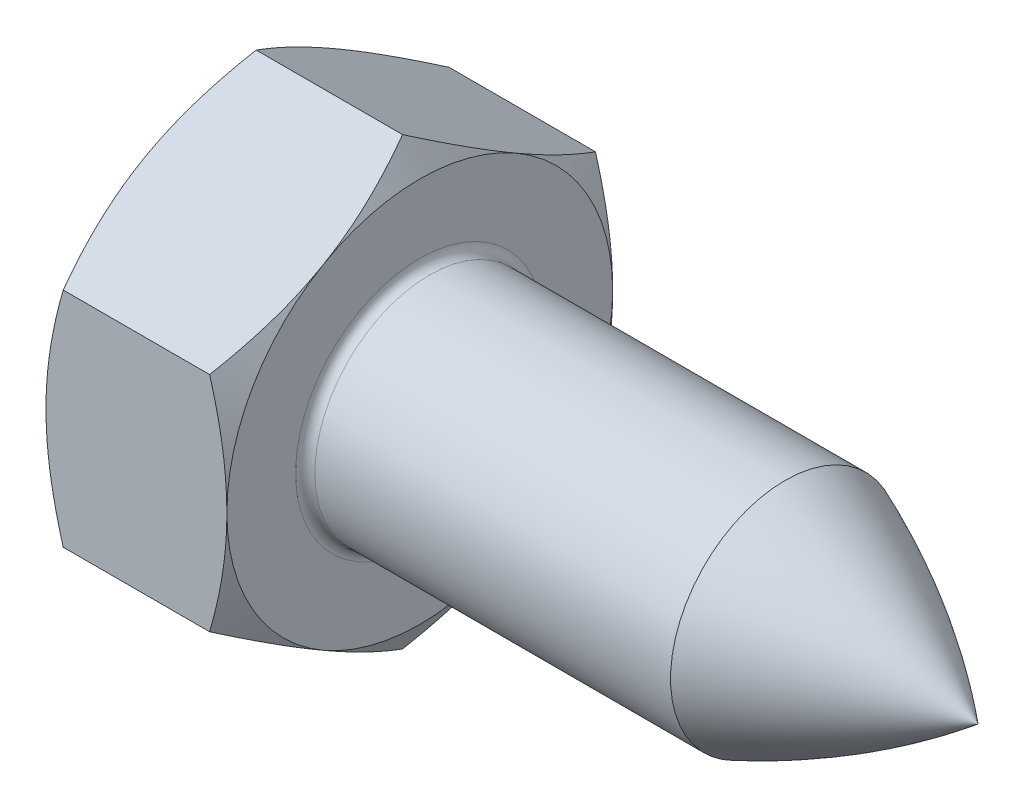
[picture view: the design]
ISO-10303-21;
HEADER;
FILE_DESCRIPTION(('STEP AP214'),'2;1');
FILE_NAME('part.step','',(''),(''),'','','');
FILE_SCHEMA(('AUTOMOTIVE_DESIGN { 1 0 10303 214 1 1 1 1 }'));
ENDSEC;
DATA;
#1=APPLICATION_CONTEXT('core data for automotive mechanical design processes');
#2=APPLICATION_PROTOCOL_DEFINITION('international standard','automotive_design',2000,#1);
#3=PRODUCT_CONTEXT('',#1,'mechanical');
#4=PRODUCT('Part','Part','',(#3));
#5=PRODUCT_RELATED_PRODUCT_CATEGORY('part','',(#4));
#6=PRODUCT_DEFINITION_FORMATION('','',#4);
#7=PRODUCT_DEFINITION_CONTEXT('part definition',#1,'design');
#8=PRODUCT_DEFINITION('design','',#6,#7);
#9=PRODUCT_DEFINITION_SHAPE('','',#8);
#10=(LENGTH_UNIT() NAMED_UNIT(*) SI_UNIT(.MILLI.,.METRE.));
#11=(NAMED_UNIT(*) PLANE_ANGLE_UNIT() SI_UNIT($,.RADIAN.));
#12=(NAMED_UNIT(*) SI_UNIT($,.STERADIAN.) SOLID_ANGLE_UNIT());
#13=UNCERTAINTY_MEASURE_WITH_UNIT(LENGTH_MEASURE(1.E-05),#10,'distance_accuracy_value','');
#14=(GEOMETRIC_REPRESENTATION_CONTEXT(3) GLOBAL_UNCERTAINTY_ASSIGNED_CONTEXT((#13)) GLOBAL_UNIT_ASSIGNED_CONTEXT((#10,
#11,#12)) REPRESENTATION_CONTEXT('',''));
#15=CARTESIAN_POINT('',(0.,0.,0.));
#16=DIRECTION('',(0.,0.,1.));
#17=DIRECTION('',(1.,0.,0.));
#18=AXIS2_PLACEMENT_3D('',#15,#16,#17);
#19=CARTESIAN_POINT('',(-9.54447010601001,0.,0.));
#20=DIRECTION('',(-1.,0.,0.));
#21=DIRECTION('',(0.,0.,1.));
#22=AXIS2_PLACEMENT_3D('',#19,#20,#21);
#23=CYLINDRICAL_SURFACE('',#22,4.75);
#24=CARTESIAN_POINT('',(7.9,0.,0.));
#25=DIRECTION('',(1.,0.,0.));
#26=DIRECTION('',(0.,0.,-1.));
#27=AXIS2_PLACEMENT_3D('',#24,#25,#26);
#28=CIRCLE('',#27,4.75);
#29=CARTESIAN_POINT('',(7.9,0.,-4.75));
#30=VERTEX_POINT('',#29);
#31=EDGE_CURVE('E12',#30,#30,#28,.T.);
#32=ORIENTED_EDGE('',*,*,#31,.T.);
#33=EDGE_LOOP('',(#32));
#34=FACE_BOUND('',#33,.T.);
#35=CARTESIAN_POINT('',(22.65,0.,0.));
#36=DIRECTION('',(1.,0.,0.));
#37=DIRECTION('',(0.,1.,0.));
#38=AXIS2_PLACEMENT_3D('',#35,#36,#37);
#39=CIRCLE('',#38,4.75);
#40=CARTESIAN_POINT('',(22.65,4.75,0.));
#41=VERTEX_POINT('',#40);
#42=EDGE_CURVE('E357',#41,#41,#39,.T.);
#43=ORIENTED_EDGE('',*,*,#42,.F.);
#44=EDGE_LOOP('',(#43));
#45=FACE_BOUND('',#44,.T.);
#46=ADVANCED_FACE('F36',(#34,#45),#23,.T.);
#47=CARTESIAN_POINT('',(7.5,13.856406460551,8.00000000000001));
#48=DIRECTION('',(1.,0.,0.));
#49=DIRECTION('',(0.,0.,-1.));
#50=AXIS2_PLACEMENT_3D('',#47,#48,#49);
#51=PLANE('',#50);
#52=CARTESIAN_POINT('',(7.5,0.,0.));
#53=DIRECTION('',(1.,0.,0.));
#54=DIRECTION('',(0.,0.,-1.));
#55=AXIS2_PLACEMENT_3D('',#52,#53,#54);
#56=CIRCLE('',#55,5.15);
#57=CARTESIAN_POINT('',(7.5,0.,-5.15));
#58=VERTEX_POINT('',#57);
#59=EDGE_CURVE('E45',#58,#58,#56,.F.);
#60=ORIENTED_EDGE('',*,*,#59,.T.);
#61=EDGE_LOOP('',(#60));
#62=FACE_BOUND('',#61,.T.);
#63=CARTESIAN_POINT('',(7.5,0.,0.));
#64=DIRECTION('',(1.,0.,0.));
#65=DIRECTION('',(0.,1.,0.));
#66=AXIS2_PLACEMENT_3D('',#63,#64,#65);
#67=CIRCLE('',#66,8.);
#68=CARTESIAN_POINT('',(7.5,-6.92820323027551,-4.));
#69=VERTEX_POINT('',#68);
#70=CARTESIAN_POINT('',(7.5,0.,-8.));
#71=VERTEX_POINT('',#70);
#72=EDGE_CURVE('E360',#69,#71,#67,.T.);
#73=ORIENTED_EDGE('',*,*,#72,.T.);
#74=CARTESIAN_POINT('',(7.5,6.92820323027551,-4.));
#75=VERTEX_POINT('',#74);
#76=EDGE_CURVE('E356',#71,#75,#67,.T.);
#77=ORIENTED_EDGE('',*,*,#76,.T.);
#78=CARTESIAN_POINT('',(7.5,6.92820323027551,4.));
#79=VERTEX_POINT('',#78);
#80=EDGE_CURVE('E351',#75,#79,#67,.T.);
#81=ORIENTED_EDGE('',*,*,#80,.T.);
#82=CARTESIAN_POINT('',(7.5,0.,8.));
#83=VERTEX_POINT('',#82);
#84=EDGE_CURVE('E52',#79,#83,#67,.T.);
#85=ORIENTED_EDGE('',*,*,#84,.T.);
#86=CARTESIAN_POINT('',(7.5,-6.92820323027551,4.));
#87=VERTEX_POINT('',#86);
#88=EDGE_CURVE('E60',#83,#87,#67,.T.);
#89=ORIENTED_EDGE('',*,*,#88,.T.);
#90=EDGE_CURVE('E354',#87,#69,#67,.T.);
#91=ORIENTED_EDGE('',*,*,#90,.T.);
#92=EDGE_LOOP('',(#73,#77,#81,#85,#89,#91));
#93=FACE_BOUND('',#92,.T.);
#94=ADVANCED_FACE('F146',(#62,#93),#51,.T.);
#95=CARTESIAN_POINT('',(6.78546882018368,0.,0.));
#96=DIRECTION('',(-1.,0.,0.));
#97=DIRECTION('',(0.,-1.,0.));
#98=AXIS2_PLACEMENT_3D('',#95,#96,#97);
#99=CONICAL_SURFACE('',#98,9.23760430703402,1.0471975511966);
#100=CARTESIAN_POINT('',(3.67178635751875,-12.2497439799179,-8.00000000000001));
#101=CARTESIAN_POINT('',(3.84152745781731,-11.8984987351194,-8.00000000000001));
#102=CARTESIAN_POINT('',(4.00958119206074,-11.5464230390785,-8.00000000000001));
#103=CARTESIAN_POINT('',(4.34134970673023,-10.840161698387,-8.00000000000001));
#104=CARTESIAN_POINT('',(4.50506373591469,-10.4859757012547,-8.00000000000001));
#105=CARTESIAN_POINT('',(4.82805107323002,-9.77313142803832,-8.00000000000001));
#106=CARTESIAN_POINT('',(4.98729360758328,-9.41445915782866,-8.00000000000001));
#107=CARTESIAN_POINT('',(5.2989388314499,-8.69416671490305,-8.00000000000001));
#108=CARTESIAN_POINT('',(5.45134187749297,-8.33254669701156,-8.00000000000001));
#109=CARTESIAN_POINT('',(5.74929869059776,-7.60129405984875,-8.00000000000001));
#110=CARTESIAN_POINT('',(5.89474539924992,-7.23161757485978,-8.));
#111=CARTESIAN_POINT('',(6.17424757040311,-6.48790521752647,-8.));
#112=CARTESIAN_POINT('',(6.30830176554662,-6.11386886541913,-8.));
#113=CARTESIAN_POINT('',(6.56141638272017,-5.36160531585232,-8.));
#114=CARTESIAN_POINT('',(6.68050868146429,-4.9833889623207,-8.));
#115=CARTESIAN_POINT('',(6.89983373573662,-4.22159300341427,-8.));
#116=CARTESIAN_POINT('',(7.0000724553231,-3.83801513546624,-8.));
#117=CARTESIAN_POINT('',(7.17681673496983,-3.06517005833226,-8.));
#118=CARTESIAN_POINT('',(7.25331597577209,-2.67590136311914,-8.));
#119=CARTESIAN_POINT('',(7.34642984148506,-2.0885729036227,-8.));
#120=CARTESIAN_POINT('',(7.37386398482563,-1.89220175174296,-8.));
#121=CARTESIAN_POINT('',(7.4209808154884,-1.49853877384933,-8.));
#122=CARTESIAN_POINT('',(7.44066427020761,-1.30124704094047,-8.));
#123=CARTESIAN_POINT('',(7.47175001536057,-0.907261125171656,-8.));
#124=CARTESIAN_POINT('',(7.48320372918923,-0.710571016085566,-8.));
#125=CARTESIAN_POINT('',(7.49776943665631,-0.316882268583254,-8.));
#126=CARTESIAN_POINT('',(7.50088153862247,-0.119883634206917,-8.));
#127=CARTESIAN_POINT('',(7.49868986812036,0.274012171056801,-8.));
#128=CARTESIAN_POINT('',(7.49338845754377,0.470909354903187,-8.));
#129=CARTESIAN_POINT('',(7.47450159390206,0.864308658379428,-8.));
#130=CARTESIAN_POINT('',(7.4609157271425,1.06081075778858,-8.));
#131=CARTESIAN_POINT('',(7.41823147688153,1.53707134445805,-8.));
#132=CARTESIAN_POINT('',(7.38498228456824,1.81646391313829,-8.));
#133=CARTESIAN_POINT('',(7.30358169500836,2.37310809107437,-8.));
#134=CARTESIAN_POINT('',(7.25542623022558,2.65035909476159,-8.));
#135=CARTESIAN_POINT('',(7.14592101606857,3.20249141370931,-8.));
#136=CARTESIAN_POINT('',(7.08455879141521,3.47737023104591,-8.));
#137=CARTESIAN_POINT('',(6.95051229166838,4.02429975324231,-8.));
#138=CARTESIAN_POINT('',(6.87782908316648,4.29635072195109,-8.));
#139=CARTESIAN_POINT('',(6.7209795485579,4.84432510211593,-8.));
#140=CARTESIAN_POINT('',(6.63657541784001,5.12017997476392,-8.));
#141=CARTESIAN_POINT('',(6.4594275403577,5.66897392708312,-8.));
#142=CARTESIAN_POINT('',(6.36668954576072,5.94191487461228,-8.));
#143=CARTESIAN_POINT('',(6.17478953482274,6.48378576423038,-8.));
#144=CARTESIAN_POINT('',(6.07566661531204,6.75272963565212,-8.));
#145=CARTESIAN_POINT('',(5.87160282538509,7.28853074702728,-8.));
#146=CARTESIAN_POINT('',(5.76665960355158,7.55538709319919,-8.));
#147=CARTESIAN_POINT('',(5.65938198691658,7.82127397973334,-8.));
#148=B_SPLINE_CURVE_WITH_KNOTS('',3,(#100,#101,#102,#103,#104,#105,#106,#107,#108,#109,#110,
#111,#112,#113,#114,#115,#116,#117,#118,#119,#120,#121,#122,#123,#124,#125,#126,#127,#128,#129,
#130,#131,#132,#133,#134,#135,#136,#137,#138,#139,#140,#141,#142,#143,#144,#145,#146,#147),
.UNSPECIFIED.,.F.,.F.,(4,2,2,2,2,2,2,2,2,2,2,2,2,2,2,2,2,2,2,2,2,2,2,4),(0.,1.17034358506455,
2.34088846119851,3.51813189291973,4.69531388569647,5.88694801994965,7.07871454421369,
8.26789729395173,9.45670322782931,10.6458253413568,11.2405311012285,11.8351779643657,
12.4260760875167,13.0169665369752,13.6076911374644,14.1984452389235,15.0420672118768,
15.8859195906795,16.7305726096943,17.5751460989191,18.4404219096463,19.3051050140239,
20.1649211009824,21.0250871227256),.UNSPECIFIED.);
#149=CARTESIAN_POINT('',(6.78546882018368,-4.61880215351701,-8.));
#150=VERTEX_POINT('',#149);
#151=EDGE_CURVE('E184',#71,#150,#148,.F.);
#152=ORIENTED_EDGE('',*,*,#151,.F.);
#153=ORIENTED_EDGE('',*,*,#72,.F.);
#154=CARTESIAN_POINT('',(6.78540215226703,-4.61868668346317,-8.0002));
#155=CARTESIAN_POINT('',(6.84400928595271,-4.72021302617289,-7.82435121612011));
#156=CARTESIAN_POINT('',(6.89995659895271,-4.82211789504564,-7.64784680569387));
#157=CARTESIAN_POINT('',(7.00579899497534,-5.02675523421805,-7.29340453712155));
#158=CARTESIAN_POINT('',(7.05569146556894,-5.12948804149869,-7.11546609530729));
#159=CARTESIAN_POINT('',(7.19530720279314,-5.43933133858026,-6.57880176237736));
#160=CARTESIAN_POINT('',(7.27471882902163,-5.64766491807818,-6.21795741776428));
#161=CARTESIAN_POINT('',(7.36783835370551,-5.95943209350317,-5.67796082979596));
#162=CARTESIAN_POINT('',(7.39436541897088,-6.06193429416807,-5.50042181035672));
#163=CARTESIAN_POINT('',(7.43884682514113,-6.26740224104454,-5.14454088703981));
#164=CARTESIAN_POINT('',(7.45680192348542,-6.37036794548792,-4.96619905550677));
#165=CARTESIAN_POINT('',(7.48368435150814,-6.57647664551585,-4.60920831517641));
#166=CARTESIAN_POINT('',(7.49262192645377,-6.67961930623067,-4.4305599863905));
#167=CARTESIAN_POINT('',(7.50127769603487,-6.88599991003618,-4.07309829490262));
#168=CARTESIAN_POINT('',(7.50099617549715,-6.98923785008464,-3.89428493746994));
#169=CARTESIAN_POINT('',(7.49185497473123,-7.18224506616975,-3.5599866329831));
#170=CARTESIAN_POINT('',(7.48411039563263,-7.27202796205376,-3.40447809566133));
#171=CARTESIAN_POINT('',(7.46179886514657,-7.45138347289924,-3.0938252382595));
#172=CARTESIAN_POINT('',(7.44723145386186,-7.5409560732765,-2.93868094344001));
#173=CARTESIAN_POINT('',(7.39363930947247,-7.80932710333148,-2.47384868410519));
#174=CARTESIAN_POINT('',(7.34473135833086,-7.98765049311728,-2.16498351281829));
#175=CARTESIAN_POINT('',(7.22246059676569,-8.34618890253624,-1.54397677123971));
#176=CARTESIAN_POINT('',(7.14857947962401,-8.52635816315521,-1.23191445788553));
#177=CARTESIAN_POINT('',(6.98089985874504,-8.88400987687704,-0.612443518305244));
#178=CARTESIAN_POINT('',(6.88714073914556,-9.06149691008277,-0.305026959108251));
#179=CARTESIAN_POINT('',(6.78540215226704,-9.23771977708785,0.000199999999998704));
#180=B_SPLINE_CURVE_WITH_KNOTS('',3,(#154,#155,#156,#157,#158,#159,#160,#161,#162,#163,#164,
#165,#166,#167,#168,#169,#170,#171,#172,#173,#174,#175,#176,#177,#178,#179),.UNSPECIFIED.,.F.,
.F.,(4,2,2,2,2,2,2,2,2,2,2,2,4),(0.,0.633973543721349,1.26821965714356,2.53934712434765,
3.15934343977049,3.77928496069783,4.39852133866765,5.01773858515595,5.55680239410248,
6.09590254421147,7.17487077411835,8.27776850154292,9.37850115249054),.UNSPECIFIED.);
#181=EDGE_CURVE('E206',#150,#69,#180,.T.);
#182=ORIENTED_EDGE('',*,*,#181,.F.);
#183=EDGE_LOOP('',(#152,#153,#182));
#184=FACE_BOUND('',#183,.T.);
#185=ADVANCED_FACE('F152',(#184),#99,.T.);
#186=ORIENTED_EDGE('',*,*,#76,.F.);
#187=CARTESIAN_POINT('',(6.78546882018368,4.61880215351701,-8.));
#188=VERTEX_POINT('',#187);
#189=EDGE_CURVE('E191',#188,#71,#148,.F.);
#190=ORIENTED_EDGE('',*,*,#189,.F.);
#191=CARTESIAN_POINT('',(6.78540215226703,9.23771977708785,0.000200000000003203));
#192=CARTESIAN_POINT('',(6.8440092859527,9.13619343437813,-0.175648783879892));
#193=CARTESIAN_POINT('',(6.89995659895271,9.03428856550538,-0.35215319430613));
#194=CARTESIAN_POINT('',(7.00579899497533,8.82965122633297,-0.706595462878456));
#195=CARTESIAN_POINT('',(7.05569146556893,8.72691841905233,-0.884533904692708));
#196=CARTESIAN_POINT('',(7.19530720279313,8.41707512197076,-1.42119823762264));
#197=CARTESIAN_POINT('',(7.27471882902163,8.20874154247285,-1.78204258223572));
#198=CARTESIAN_POINT('',(7.36783835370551,7.89697436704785,-2.32203917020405));
#199=CARTESIAN_POINT('',(7.39436541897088,7.79447216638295,-2.49957818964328));
#200=CARTESIAN_POINT('',(7.43884682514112,7.58900421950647,-2.8554591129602));
#201=CARTESIAN_POINT('',(7.45680192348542,7.4860385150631,-3.03380094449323));
#202=CARTESIAN_POINT('',(7.48368435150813,7.27992981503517,-3.39079168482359));
#203=CARTESIAN_POINT('',(7.49262192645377,7.17678715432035,-3.5694400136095));
#204=CARTESIAN_POINT('',(7.50127769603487,6.97040655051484,-3.92690170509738));
#205=CARTESIAN_POINT('',(7.50099617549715,6.86716861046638,-4.10571506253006));
#206=CARTESIAN_POINT('',(7.49185497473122,6.67416139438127,-4.4400133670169));
#207=CARTESIAN_POINT('',(7.48411039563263,6.58437849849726,-4.59552190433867));
#208=CARTESIAN_POINT('',(7.46179886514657,6.40502298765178,-4.90617476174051));
#209=CARTESIAN_POINT('',(7.44723145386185,6.31545038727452,-5.06131905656));
#210=CARTESIAN_POINT('',(7.39363930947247,6.04707935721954,-5.52615131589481));
#211=CARTESIAN_POINT('',(7.34473135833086,5.86875596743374,-5.83501648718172));
#212=CARTESIAN_POINT('',(7.22246059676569,5.51021755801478,-6.4560232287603));
#213=CARTESIAN_POINT('',(7.14857947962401,5.33004829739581,-6.76808554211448));
#214=CARTESIAN_POINT('',(6.98089985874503,4.97239658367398,-7.38755648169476));
#215=CARTESIAN_POINT('',(6.88714073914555,4.79490955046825,-7.69497304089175));
#216=CARTESIAN_POINT('',(6.78540215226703,4.61868668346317,-8.0002));
#217=B_SPLINE_CURVE_WITH_KNOTS('',3,(#191,#192,#193,#194,#195,#196,#197,#198,#199,#200,#201,
#202,#203,#204,#205,#206,#207,#208,#209,#210,#211,#212,#213,#214,#215,#216),.UNSPECIFIED.,.F.,
.F.,(4,2,2,2,2,2,2,2,2,2,2,2,4),(0.,0.633973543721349,1.26821965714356,2.53934712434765,
3.15934343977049,3.77928496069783,4.39852133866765,5.01773858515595,5.55680239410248,
6.09590254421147,7.17487077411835,8.27776850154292,9.37850115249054),.UNSPECIFIED.);
#218=EDGE_CURVE('E213',#75,#188,#217,.T.);
#219=ORIENTED_EDGE('',*,*,#218,.F.);
#220=EDGE_LOOP('',(#186,#190,#219));
#221=FACE_BOUND('',#220,.T.);
#222=ADVANCED_FACE('F519',(#221),#99,.T.);
#223=CARTESIAN_POINT('',(6.78546882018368,-9.23760430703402,0.));
#224=VERTEX_POINT('',#223);
#225=EDGE_CURVE('E336',#69,#224,#180,.T.);
#226=ORIENTED_EDGE('',*,*,#225,.F.);
#227=ORIENTED_EDGE('',*,*,#90,.F.);
#228=CARTESIAN_POINT('',(6.78540215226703,-9.23771977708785,-0.000200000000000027));
#229=CARTESIAN_POINT('',(6.84400928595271,-9.13619343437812,0.175648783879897));
#230=CARTESIAN_POINT('',(6.89995659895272,-9.03428856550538,0.352153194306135));
#231=CARTESIAN_POINT('',(7.00579899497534,-8.82965122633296,0.706595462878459));
#232=CARTESIAN_POINT('',(7.05569146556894,-8.72691841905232,0.884533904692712));
#233=CARTESIAN_POINT('',(7.19530720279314,-8.41707512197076,1.42119823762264));
#234=CARTESIAN_POINT('',(7.27471882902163,-8.20874154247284,1.78204258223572));
#235=CARTESIAN_POINT('',(7.36783835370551,-7.89697436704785,2.32203917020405));
#236=CARTESIAN_POINT('',(7.39436541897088,-7.79447216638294,2.49957818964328));
#237=CARTESIAN_POINT('',(7.43884682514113,-7.58900421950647,2.8554591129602));
#238=CARTESIAN_POINT('',(7.45680192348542,-7.4860385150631,3.03380094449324));
#239=CARTESIAN_POINT('',(7.48368435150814,-7.27992981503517,3.39079168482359));
#240=CARTESIAN_POINT('',(7.49262192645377,-7.17678715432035,3.5694400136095));
#241=CARTESIAN_POINT('',(7.50127769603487,-6.97040655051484,3.92690170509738));
#242=CARTESIAN_POINT('',(7.50099617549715,-6.86716861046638,4.10571506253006));
#243=CARTESIAN_POINT('',(7.49185497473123,-6.67416139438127,4.4400133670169));
#244=CARTESIAN_POINT('',(7.48411039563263,-6.58437849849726,4.59552190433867));
#245=CARTESIAN_POINT('',(7.46179886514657,-6.40502298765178,4.90617476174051));
#246=CARTESIAN_POINT('',(7.44723145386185,-6.31545038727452,5.06131905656));
#247=CARTESIAN_POINT('',(7.39363930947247,-6.04707935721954,5.52615131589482));
#248=CARTESIAN_POINT('',(7.34473135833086,-5.86875596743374,5.83501648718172));
#249=CARTESIAN_POINT('',(7.22246059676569,-5.51021755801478,6.4560232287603));
#250=CARTESIAN_POINT('',(7.14857947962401,-5.33004829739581,6.76808554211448));
#251=CARTESIAN_POINT('',(6.98089985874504,-4.97239658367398,7.38755648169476));
#252=CARTESIAN_POINT('',(6.88714073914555,-4.79490955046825,7.69497304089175));
#253=CARTESIAN_POINT('',(6.78540215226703,-4.61868668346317,8.0002));
#254=B_SPLINE_CURVE_WITH_KNOTS('',3,(#228,#229,#230,#231,#232,#233,#234,#235,#236,#237,#238,
#239,#240,#241,#242,#243,#244,#245,#246,#247,#248,#249,#250,#251,#252,#253),.UNSPECIFIED.,.F.,
.F.,(4,2,2,2,2,2,2,2,2,2,2,2,4),(0.,0.63397354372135,1.26821965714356,2.53934712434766,
3.15934343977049,3.77928496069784,4.39852133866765,5.01773858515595,5.55680239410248,
6.09590254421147,7.17487077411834,8.27776850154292,9.37850115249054),.UNSPECIFIED.);
#255=EDGE_CURVE('E218',#224,#87,#254,.T.);
#256=ORIENTED_EDGE('',*,*,#255,.F.);
#257=EDGE_LOOP('',(#226,#227,#256));
#258=FACE_BOUND('',#257,.T.);
#259=ADVANCED_FACE('F199',(#258),#99,.T.);
#260=CARTESIAN_POINT('',(6.78546882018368,-4.61880215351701,8.));
#261=VERTEX_POINT('',#260);
#262=EDGE_CURVE('E346',#87,#261,#254,.T.);
#263=ORIENTED_EDGE('',*,*,#262,.F.);
#264=ORIENTED_EDGE('',*,*,#88,.F.);
#265=CARTESIAN_POINT('',(3.67178635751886,-12.2497439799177,7.99999999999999));
#266=CARTESIAN_POINT('',(3.84152745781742,-11.8984987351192,8.));
#267=CARTESIAN_POINT('',(4.00958119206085,-11.5464230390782,8.));
#268=CARTESIAN_POINT('',(4.34134970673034,-10.8401616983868,8.));
#269=CARTESIAN_POINT('',(4.50506373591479,-10.4859757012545,8.));
#270=CARTESIAN_POINT('',(4.82805107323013,-9.7731314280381,8.));
#271=CARTESIAN_POINT('',(4.98729360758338,-9.41445915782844,8.));
#272=CARTESIAN_POINT('',(5.29893883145,-8.69416671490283,8.));
#273=CARTESIAN_POINT('',(5.45134187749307,-8.33254669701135,8.));
#274=CARTESIAN_POINT('',(5.74929869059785,-7.60129405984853,8.));
#275=CARTESIAN_POINT('',(5.89474539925,-7.23161757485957,8.));
#276=CARTESIAN_POINT('',(6.17424757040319,-6.48790521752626,8.));
#277=CARTESIAN_POINT('',(6.3083017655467,-6.11386886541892,8.));
#278=CARTESIAN_POINT('',(6.56141638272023,-5.36160531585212,8.));
#279=CARTESIAN_POINT('',(6.68050868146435,-4.9833889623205,8.));
#280=CARTESIAN_POINT('',(6.89983373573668,-4.22159300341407,8.));
#281=CARTESIAN_POINT('',(7.00007245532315,-3.83801513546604,8.));
#282=CARTESIAN_POINT('',(7.17681673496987,-3.06517005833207,8.));
#283=CARTESIAN_POINT('',(7.25331597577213,-2.67590136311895,8.));
#284=CARTESIAN_POINT('',(7.34642984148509,-2.0885729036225,8.));
#285=CARTESIAN_POINT('',(7.37386398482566,-1.89220175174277,8.));
#286=CARTESIAN_POINT('',(7.42098081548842,-1.49853877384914,8.));
#287=CARTESIAN_POINT('',(7.44066427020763,-1.30124704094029,8.));
#288=CARTESIAN_POINT('',(7.47175001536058,-0.907261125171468,8.));
#289=CARTESIAN_POINT('',(7.48320372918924,-0.710571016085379,8.));
#290=CARTESIAN_POINT('',(7.49776943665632,-0.31688226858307,8.));
#291=CARTESIAN_POINT('',(7.50088153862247,-0.119883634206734,8.));
#292=CARTESIAN_POINT('',(7.49868986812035,0.274012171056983,8.));
#293=CARTESIAN_POINT('',(7.49338845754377,0.470909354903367,8.));
#294=CARTESIAN_POINT('',(7.47450159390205,0.864308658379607,8.));
#295=CARTESIAN_POINT('',(7.46091572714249,1.06081075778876,8.));
#296=CARTESIAN_POINT('',(7.41823147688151,1.53707134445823,8.));
#297=CARTESIAN_POINT('',(7.38498228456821,1.81646391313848,8.));
#298=CARTESIAN_POINT('',(7.30358169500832,2.37310809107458,8.));
#299=CARTESIAN_POINT('',(7.25542623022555,2.6503590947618,8.));
#300=CARTESIAN_POINT('',(7.14592101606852,3.20249141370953,8.));
#301=CARTESIAN_POINT('',(7.08455879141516,3.47737023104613,8.));
#302=CARTESIAN_POINT('',(6.95051229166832,4.02429975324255,8.));
#303=CARTESIAN_POINT('',(6.87782908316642,4.29635072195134,8.));
#304=CARTESIAN_POINT('',(6.72097954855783,4.84432510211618,8.));
#305=CARTESIAN_POINT('',(6.63657541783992,5.12017997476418,8.));
#306=CARTESIAN_POINT('',(6.4594275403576,5.66897392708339,8.));
#307=CARTESIAN_POINT('',(6.36668954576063,5.94191487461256,8.));
#308=CARTESIAN_POINT('',(6.17478953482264,6.48378576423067,8.));
#309=CARTESIAN_POINT('',(6.07566661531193,6.75272963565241,8.));
#310=CARTESIAN_POINT('',(5.87160282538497,7.28853074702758,8.));
#311=CARTESIAN_POINT('',(5.76665960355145,7.5553870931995,8.));
#312=CARTESIAN_POINT('',(5.65938198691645,7.82127397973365,8.));
#313=B_SPLINE_CURVE_WITH_KNOTS('',3,(#265,#266,#267,#268,#269,#270,#271,#272,#273,#274,#275,
#276,#277,#278,#279,#280,#281,#282,#283,#284,#285,#286,#287,#288,#289,#290,#291,#292,#293,#294,
#295,#296,#297,#298,#299,#300,#301,#302,#303,#304,#305,#306,#307,#308,#309,#310,#311,#312),
.UNSPECIFIED.,.F.,.F.,(4,2,2,2,2,2,2,2,2,2,2,2,2,2,2,2,2,2,2,2,2,2,2,4),(0.,1.17034358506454,
2.3408884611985,3.51813189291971,4.69531388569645,5.88694801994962,7.07871454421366,
8.26789729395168,9.45670322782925,10.6458253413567,11.2405311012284,11.8351779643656,
12.4260760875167,13.0169665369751,13.6076911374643,14.1984452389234,15.0420672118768,
15.8859195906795,16.7305726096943,17.5751460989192,18.4404219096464,19.305105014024,
20.1649211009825,21.0250871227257),.UNSPECIFIED.);
#314=EDGE_CURVE('E344',#261,#83,#313,.T.);
#315=ORIENTED_EDGE('',*,*,#314,.F.);
#316=EDGE_LOOP('',(#263,#264,#315));
#317=FACE_BOUND('',#316,.T.);
#318=ADVANCED_FACE('F195',(#317),#99,.T.);
#319=ORIENTED_EDGE('',*,*,#84,.F.);
#320=CARTESIAN_POINT('',(6.78540215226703,4.61868668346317,8.0002));
#321=CARTESIAN_POINT('',(6.84400928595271,4.72021302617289,7.82435121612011));
#322=CARTESIAN_POINT('',(6.89995659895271,4.82211789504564,7.64784680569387));
#323=CARTESIAN_POINT('',(7.00579899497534,5.02675523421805,7.29340453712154));
#324=CARTESIAN_POINT('',(7.05569146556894,5.12948804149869,7.11546609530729));
#325=CARTESIAN_POINT('',(7.19530720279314,5.43933133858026,6.57880176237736));
#326=CARTESIAN_POINT('',(7.27471882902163,5.64766491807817,6.21795741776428));
#327=CARTESIAN_POINT('',(7.36783835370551,5.95943209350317,5.67796082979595));
#328=CARTESIAN_POINT('',(7.39436541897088,6.06193429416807,5.50042181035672));
#329=CARTESIAN_POINT('',(7.43884682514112,6.26740224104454,5.14454088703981));
#330=CARTESIAN_POINT('',(7.45680192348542,6.37036794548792,4.96619905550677));
#331=CARTESIAN_POINT('',(7.48368435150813,6.57647664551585,4.60920831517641));
#332=CARTESIAN_POINT('',(7.49262192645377,6.67961930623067,4.4305599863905));
#333=CARTESIAN_POINT('',(7.50127769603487,6.88599991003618,4.07309829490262));
#334=CARTESIAN_POINT('',(7.50099617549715,6.98923785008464,3.89428493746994));
#335=CARTESIAN_POINT('',(7.49185497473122,7.18224506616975,3.5599866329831));
#336=CARTESIAN_POINT('',(7.48411039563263,7.27202796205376,3.40447809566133));
#337=CARTESIAN_POINT('',(7.46179886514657,7.45138347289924,3.09382523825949));
#338=CARTESIAN_POINT('',(7.44723145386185,7.5409560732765,2.93868094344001));
#339=CARTESIAN_POINT('',(7.39363930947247,7.80932710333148,2.47384868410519));
#340=CARTESIAN_POINT('',(7.34473135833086,7.98765049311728,2.16498351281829));
#341=CARTESIAN_POINT('',(7.22246059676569,8.34618890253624,1.54397677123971));
#342=CARTESIAN_POINT('',(7.14857947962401,8.52635816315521,1.23191445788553));
#343=CARTESIAN_POINT('',(6.98089985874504,8.88400987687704,0.612443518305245));
#344=CARTESIAN_POINT('',(6.88714073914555,9.06149691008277,0.305026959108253));
#345=CARTESIAN_POINT('',(6.78540215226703,9.23771977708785,-0.000199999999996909));
#346=B_SPLINE_CURVE_WITH_KNOTS('',3,(#320,#321,#322,#323,#324,#325,#326,#327,#328,#329,#330,
#331,#332,#333,#334,#335,#336,#337,#338,#339,#340,#341,#342,#343,#344,#345),.UNSPECIFIED.,.F.,
.F.,(4,2,2,2,2,2,2,2,2,2,2,2,4),(0.,0.633973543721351,1.26821965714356,2.53934712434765,
3.15934343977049,3.77928496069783,4.39852133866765,5.01773858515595,5.55680239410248,
6.09590254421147,7.17487077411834,8.27776850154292,9.37850115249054),.UNSPECIFIED.);
#347=CARTESIAN_POINT('',(6.78546882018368,4.618802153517,8.));
#348=VERTEX_POINT('',#347);
#349=EDGE_CURVE('E229',#348,#79,#346,.T.);
#350=ORIENTED_EDGE('',*,*,#349,.F.);
#351=EDGE_CURVE('E230',#83,#348,#313,.T.);
#352=ORIENTED_EDGE('',*,*,#351,.F.);
#353=EDGE_LOOP('',(#319,#350,#352));
#354=FACE_BOUND('',#353,.T.);
#355=ADVANCED_FACE('F198',(#354),#99,.T.);
#356=ORIENTED_EDGE('',*,*,#80,.F.);
#357=CARTESIAN_POINT('',(6.78546882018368,9.23760430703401,0.));
#358=VERTEX_POINT('',#357);
#359=EDGE_CURVE('E348',#358,#75,#217,.T.);
#360=ORIENTED_EDGE('',*,*,#359,.F.);
#361=EDGE_CURVE('E223',#79,#358,#346,.T.);
#362=ORIENTED_EDGE('',*,*,#361,.F.);
#363=EDGE_LOOP('',(#356,#360,#362));
#364=FACE_BOUND('',#363,.T.);
#365=ADVANCED_FACE('F164',(#364),#99,.T.);
#366=CARTESIAN_POINT('',(0.,13.856406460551,8.00000000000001));
#367=DIRECTION('',(1.,0.,0.));
#368=DIRECTION('',(0.,0.,-1.));
#369=AXIS2_PLACEMENT_3D('',#366,#367,#368);
#370=PLANE('',#369);
#371=CARTESIAN_POINT('',(0.,0.,0.));
#372=DIRECTION('',(1.,0.,0.));
#373=DIRECTION('',(0.,0.,-1.));
#374=AXIS2_PLACEMENT_3D('',#371,#372,#373);
#375=CIRCLE('',#374,6.66666666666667);
#376=CARTESIAN_POINT('',(0.,0.,-6.66666666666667));
#377=VERTEX_POINT('',#376);
#378=EDGE_CURVE('E40',#377,#377,#375,.T.);
#379=ORIENTED_EDGE('',*,*,#378,.T.);
#380=EDGE_LOOP('',(#379));
#381=FACE_BOUND('',#380,.T.);
#382=CARTESIAN_POINT('',(0.,0.,0.));
#383=DIRECTION('',(1.,0.,0.));
#384=DIRECTION('',(0.,0.,-1.));
#385=AXIS2_PLACEMENT_3D('',#382,#383,#384);
#386=CIRCLE('',#385,8.);
#387=CARTESIAN_POINT('',(0.,6.92820323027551,-4.));
#388=VERTEX_POINT('',#387);
#389=CARTESIAN_POINT('',(0.,0.,-8.));
#390=VERTEX_POINT('',#389);
#391=EDGE_CURVE('E193',#388,#390,#386,.F.);
#392=ORIENTED_EDGE('',*,*,#391,.T.);
#393=CARTESIAN_POINT('',(0.,-6.92820323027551,-4.));
#394=VERTEX_POINT('',#393);
#395=EDGE_CURVE('E192',#390,#394,#386,.F.);
#396=ORIENTED_EDGE('',*,*,#395,.T.);
#397=CARTESIAN_POINT('',(0.,-6.92820323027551,4.));
#398=VERTEX_POINT('',#397);
#399=EDGE_CURVE('E286',#394,#398,#386,.F.);
#400=ORIENTED_EDGE('',*,*,#399,.T.);
#401=CARTESIAN_POINT('',(0.,0.,8.));
#402=VERTEX_POINT('',#401);
#403=EDGE_CURVE('E285',#398,#402,#386,.F.);
#404=ORIENTED_EDGE('',*,*,#403,.T.);
#405=CARTESIAN_POINT('',(0.,0.,0.));
#406=DIRECTION('',(1.,0.,0.));
#407=DIRECTION('',(0.,1.,0.));
#408=AXIS2_PLACEMENT_3D('',#405,#406,#407);
#409=CIRCLE('',#408,8.);
#410=CARTESIAN_POINT('',(0.,6.92820323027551,4.));
#411=VERTEX_POINT('',#410);
#412=EDGE_CURVE('E296',#411,#402,#409,.T.);
#413=ORIENTED_EDGE('',*,*,#412,.F.);
#414=EDGE_CURVE('E279',#411,#388,#386,.F.);
#415=ORIENTED_EDGE('',*,*,#414,.T.);
#416=EDGE_LOOP('',(#392,#396,#400,#404,#413,#415));
#417=FACE_BOUND('',#416,.T.);
#418=ADVANCED_FACE('F160',(#381,#417),#370,.F.);
#419=CARTESIAN_POINT('',(0.,0.,0.));
#420=DIRECTION('',(1.,0.,0.));
#421=DIRECTION('',(0.,1.,0.));
#422=AXIS2_PLACEMENT_3D('',#419,#420,#421);
#423=CONICAL_SURFACE('',#422,8.,1.0471975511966);
#424=ORIENTED_EDGE('',*,*,#414,.F.);
#425=CARTESIAN_POINT('',(0.714597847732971,9.23771977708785,-0.000199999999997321));
#426=CARTESIAN_POINT('',(0.655990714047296,9.13619343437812,0.175648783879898));
#427=CARTESIAN_POINT('',(0.600043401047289,9.03428856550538,0.352153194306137));
#428=CARTESIAN_POINT('',(0.494201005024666,8.82965122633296,0.706595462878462));
#429=CARTESIAN_POINT('',(0.444308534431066,8.72691841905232,0.884533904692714));
#430=CARTESIAN_POINT('',(0.304692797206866,8.41707512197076,1.42119823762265));
#431=CARTESIAN_POINT('',(0.225281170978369,8.20874154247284,1.78204258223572));
#432=CARTESIAN_POINT('',(0.132161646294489,7.89697436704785,2.32203917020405));
#433=CARTESIAN_POINT('',(0.105634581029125,7.79447216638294,2.49957818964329));
#434=CARTESIAN_POINT('',(0.061153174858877,7.58900421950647,2.8554591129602));
#435=CARTESIAN_POINT('',(0.0431980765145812,7.4860385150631,3.03380094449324));
#436=CARTESIAN_POINT('',(0.0163156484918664,7.27992981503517,3.39079168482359));
#437=CARTESIAN_POINT('',(0.00737807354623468,7.17678715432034,3.5694400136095));
#438=CARTESIAN_POINT('',(-0.00127769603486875,6.97040655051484,3.92690170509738));
#439=CARTESIAN_POINT('',(-0.000996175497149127,6.86716861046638,4.10571506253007));
#440=CARTESIAN_POINT('',(0.00814502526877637,6.67416139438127,4.44001336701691));
#441=CARTESIAN_POINT('',(0.0158896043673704,6.58437849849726,4.59552190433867));
#442=CARTESIAN_POINT('',(0.0382011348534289,6.40502298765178,4.90617476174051));
#443=CARTESIAN_POINT('',(0.0527685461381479,6.31545038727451,5.06131905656));
#444=CARTESIAN_POINT('',(0.106360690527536,6.04707935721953,5.52615131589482));
#445=CARTESIAN_POINT('',(0.155268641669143,5.86875596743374,5.83501648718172));
#446=CARTESIAN_POINT('',(0.277539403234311,5.51021755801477,6.4560232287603));
#447=CARTESIAN_POINT('',(0.351420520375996,5.3300482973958,6.76808554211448));
#448=CARTESIAN_POINT('',(0.519100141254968,4.97239658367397,7.38755648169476));
#449=CARTESIAN_POINT('',(0.612859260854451,4.79490955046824,7.69497304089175));
#450=CARTESIAN_POINT('',(0.714597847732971,4.61868668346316,8.0002));
#451=B_SPLINE_CURVE_WITH_KNOTS('',3,(#425,#426,#427,#428,#429,#430,#431,#432,#433,#434,#435,
#436,#437,#438,#439,#440,#441,#442,#443,#444,#445,#446,#447,#448,#449,#450),.UNSPECIFIED.,.F.,
.F.,(4,2,2,2,2,2,2,2,2,2,2,2,4),(0.,0.63397354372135,1.26821965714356,2.53934712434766,
3.15934343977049,3.77928496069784,4.39852133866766,5.01773858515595,5.55680239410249,
6.09590254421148,7.17487077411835,8.27776850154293,9.37850115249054),.UNSPECIFIED.);
#452=CARTESIAN_POINT('',(0.71453117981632,9.23760430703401,0.));
#453=VERTEX_POINT('',#452);
#454=EDGE_CURVE('E251',#453,#411,#451,.T.);
#455=ORIENTED_EDGE('',*,*,#454,.F.);
#456=CARTESIAN_POINT('',(0.714597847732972,4.61868668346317,-8.0002));
#457=CARTESIAN_POINT('',(0.655990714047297,4.7202130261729,-7.8243512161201));
#458=CARTESIAN_POINT('',(0.60004340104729,4.82211789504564,-7.64784680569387));
#459=CARTESIAN_POINT('',(0.494201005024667,5.02675523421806,-7.29340453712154));
#460=CARTESIAN_POINT('',(0.444308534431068,5.1294880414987,-7.11546609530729));
#461=CARTESIAN_POINT('',(0.304692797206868,5.43933133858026,-6.57880176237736));
#462=CARTESIAN_POINT('',(0.22528117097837,5.64766491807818,-6.21795741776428));
#463=CARTESIAN_POINT('',(0.132161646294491,5.95943209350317,-5.67796082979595));
#464=CARTESIAN_POINT('',(0.105634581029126,6.06193429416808,-5.50042181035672));
#465=CARTESIAN_POINT('',(0.0611531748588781,6.26740224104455,-5.1445408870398));
#466=CARTESIAN_POINT('',(0.043198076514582,6.37036794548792,-4.96619905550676));
#467=CARTESIAN_POINT('',(0.0163156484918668,6.57647664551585,-4.60920831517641));
#468=CARTESIAN_POINT('',(0.00737807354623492,6.67961930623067,-4.4305599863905));
#469=CARTESIAN_POINT('',(-0.0012776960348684,6.88599991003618,-4.07309829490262));
#470=CARTESIAN_POINT('',(-0.000996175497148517,6.98923785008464,-3.89428493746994));
#471=CARTESIAN_POINT('',(0.00814502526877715,7.18224506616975,-3.5599866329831));
#472=CARTESIAN_POINT('',(0.0158896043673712,7.27202796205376,-3.40447809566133));
#473=CARTESIAN_POINT('',(0.0382011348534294,7.45138347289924,-3.09382523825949));
#474=CARTESIAN_POINT('',(0.0527685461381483,7.5409560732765,-2.93868094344));
#475=CARTESIAN_POINT('',(0.106360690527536,7.80932710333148,-2.47384868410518));
#476=CARTESIAN_POINT('',(0.155268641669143,7.98765049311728,-2.16498351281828));
#477=CARTESIAN_POINT('',(0.277539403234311,8.34618890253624,-1.5439767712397));
#478=CARTESIAN_POINT('',(0.351420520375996,8.52635816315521,-1.23191445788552));
#479=CARTESIAN_POINT('',(0.519100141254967,8.88400987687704,-0.612443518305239));
#480=CARTESIAN_POINT('',(0.61285926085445,9.06149691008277,-0.305026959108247));
#481=CARTESIAN_POINT('',(0.71459784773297,9.23771977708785,0.000200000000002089));
#482=B_SPLINE_CURVE_WITH_KNOTS('',3,(#456,#457,#458,#459,#460,#461,#462,#463,#464,#465,#466,
#467,#468,#469,#470,#471,#472,#473,#474,#475,#476,#477,#478,#479,#480,#481),.UNSPECIFIED.,.F.,
.F.,(4,2,2,2,2,2,2,2,2,2,2,2,4),(0.,0.633973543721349,1.26821965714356,2.53934712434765,
3.15934343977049,3.77928496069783,4.39852133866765,5.01773858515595,5.55680239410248,
6.09590254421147,7.17487077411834,8.27776850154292,9.37850115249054),.UNSPECIFIED.);
#483=EDGE_CURVE('E258',#388,#453,#482,.T.);
#484=ORIENTED_EDGE('',*,*,#483,.F.);
#485=EDGE_LOOP('',(#424,#455,#484));
#486=FACE_BOUND('',#485,.T.);
#487=ADVANCED_FACE('F163',(#486),#423,.T.);
#488=ORIENTED_EDGE('',*,*,#412,.T.);
#489=CARTESIAN_POINT('',(3.82821364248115,-12.2497439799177,7.99999999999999));
#490=CARTESIAN_POINT('',(3.65847254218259,-11.8984987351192,8.));
#491=CARTESIAN_POINT('',(3.49041880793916,-11.5464230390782,8.));
#492=CARTESIAN_POINT('',(3.15865029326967,-10.8401616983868,8.));
#493=CARTESIAN_POINT('',(2.99493626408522,-10.4859757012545,8.));
#494=CARTESIAN_POINT('',(2.67194892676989,-9.7731314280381,8.));
#495=CARTESIAN_POINT('',(2.51270639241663,-9.41445915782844,8.));
#496=CARTESIAN_POINT('',(2.20106116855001,-8.69416671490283,8.));
#497=CARTESIAN_POINT('',(2.04865812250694,-8.33254669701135,8.));
#498=CARTESIAN_POINT('',(1.75070130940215,-7.60129405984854,8.));
#499=CARTESIAN_POINT('',(1.60525460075,-7.23161757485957,8.));
#500=CARTESIAN_POINT('',(1.32575242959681,-6.48790521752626,8.));
#501=CARTESIAN_POINT('',(1.19169823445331,-6.11386886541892,8.));
#502=CARTESIAN_POINT('',(0.938583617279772,-5.36160531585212,8.));
#503=CARTESIAN_POINT('',(0.819491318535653,-4.9833889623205,8.));
#504=CARTESIAN_POINT('',(0.600166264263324,-4.22159300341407,8.));
#505=CARTESIAN_POINT('',(0.49992754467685,-3.83801513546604,8.));
#506=CARTESIAN_POINT('',(0.323183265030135,-3.06517005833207,8.));
#507=CARTESIAN_POINT('',(0.246684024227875,-2.67590136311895,8.));
#508=CARTESIAN_POINT('',(0.15357015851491,-2.0885729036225,8.));
#509=CARTESIAN_POINT('',(0.126136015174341,-1.89220175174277,8.));
#510=CARTESIAN_POINT('',(0.0790191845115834,-1.49853877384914,8.));
#511=CARTESIAN_POINT('',(0.0593357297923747,-1.30124704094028,8.));
#512=CARTESIAN_POINT('',(0.0282499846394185,-0.907261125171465,8.));
#513=CARTESIAN_POINT('',(0.0167962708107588,-0.710571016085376,8.));
#514=CARTESIAN_POINT('',(0.00223056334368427,-0.316882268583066,8.));
#515=CARTESIAN_POINT('',(-0.00088153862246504,-0.11988363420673,8.));
#516=CARTESIAN_POINT('',(0.00131013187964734,0.274012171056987,8.));
#517=CARTESIAN_POINT('',(0.00661154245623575,0.470909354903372,8.));
#518=CARTESIAN_POINT('',(0.0254984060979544,0.864308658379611,8.));
#519=CARTESIAN_POINT('',(0.0390842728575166,1.06081075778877,8.));
#520=CARTESIAN_POINT('',(0.0817685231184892,1.53707134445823,8.));
#521=CARTESIAN_POINT('',(0.115017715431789,1.81646391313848,8.));
#522=CARTESIAN_POINT('',(0.196418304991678,2.37310809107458,8.));
#523=CARTESIAN_POINT('',(0.244573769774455,2.6503590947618,8.));
#524=CARTESIAN_POINT('',(0.354078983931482,3.20249141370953,8.));
#525=CARTESIAN_POINT('',(0.415441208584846,3.47737023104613,8.));
#526=CARTESIAN_POINT('',(0.549487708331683,4.02429975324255,8.));
#527=CARTESIAN_POINT('',(0.622170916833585,4.29635072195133,8.));
#528=CARTESIAN_POINT('',(0.779020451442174,4.84432510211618,8.));
#529=CARTESIAN_POINT('',(0.863424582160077,5.12017997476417,8.));
#530=CARTESIAN_POINT('',(1.0405724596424,5.66897392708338,8.));
#531=CARTESIAN_POINT('',(1.13331045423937,5.94191487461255,8.));
#532=CARTESIAN_POINT('',(1.32521046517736,6.48378576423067,8.));
#533=CARTESIAN_POINT('',(1.42433338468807,6.75272963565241,8.));
#534=CARTESIAN_POINT('',(1.62839717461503,7.28853074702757,8.));
#535=CARTESIAN_POINT('',(1.73334039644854,7.55538709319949,8.));
#536=CARTESIAN_POINT('',(1.84061801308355,7.82127397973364,8.));
#537=B_SPLINE_CURVE_WITH_KNOTS('',3,(#489,#490,#491,#492,#493,#494,#495,#496,#497,#498,#499,
#500,#501,#502,#503,#504,#505,#506,#507,#508,#509,#510,#511,#512,#513,#514,#515,#516,#517,#518,
#519,#520,#521,#522,#523,#524,#525,#526,#527,#528,#529,#530,#531,#532,#533,#534,#535,#536),
.UNSPECIFIED.,.F.,.F.,(4,2,2,2,2,2,2,2,2,2,2,2,2,2,2,2,2,2,2,2,2,2,2,4),(0.,1.17034358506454,
2.34088846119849,3.51813189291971,4.69531388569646,5.88694801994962,7.07871454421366,
8.26789729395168,9.45670322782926,10.6458253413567,11.2405311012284,11.8351779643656,
12.4260760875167,13.0169665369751,13.6076911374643,14.1984452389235,15.0420672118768,
15.8859195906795,16.7305726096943,17.5751460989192,18.4404219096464,19.305105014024,
20.1649211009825,21.0250871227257),.UNSPECIFIED.);
#538=CARTESIAN_POINT('',(0.71453117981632,4.61880215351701,8.));
#539=VERTEX_POINT('',#538);
#540=EDGE_CURVE('E252',#539,#402,#537,.F.);
#541=ORIENTED_EDGE('',*,*,#540,.F.);
#542=EDGE_CURVE('E244',#411,#539,#451,.T.);
#543=ORIENTED_EDGE('',*,*,#542,.F.);
#544=EDGE_LOOP('',(#488,#541,#543));
#545=FACE_BOUND('',#544,.T.);
#546=ADVANCED_FACE('F477',(#545),#423,.T.);
#547=ORIENTED_EDGE('',*,*,#403,.F.);
#548=CARTESIAN_POINT('',(0.714597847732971,-4.61868668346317,8.0002));
#549=CARTESIAN_POINT('',(0.655990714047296,-4.7202130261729,7.8243512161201));
#550=CARTESIAN_POINT('',(0.600043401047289,-4.82211789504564,7.64784680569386));
#551=CARTESIAN_POINT('',(0.494201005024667,-5.02675523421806,7.29340453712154));
#552=CARTESIAN_POINT('',(0.444308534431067,-5.1294880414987,7.11546609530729));
#553=CARTESIAN_POINT('',(0.304692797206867,-5.43933133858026,6.57880176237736));
#554=CARTESIAN_POINT('',(0.225281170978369,-5.64766491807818,6.21795741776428));
#555=CARTESIAN_POINT('',(0.13216164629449,-5.95943209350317,5.67796082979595));
#556=CARTESIAN_POINT('',(0.105634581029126,-6.06193429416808,5.50042181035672));
#557=CARTESIAN_POINT('',(0.0611531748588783,-6.26740224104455,5.1445408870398));
#558=CARTESIAN_POINT('',(0.0431980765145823,-6.37036794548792,4.96619905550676));
#559=CARTESIAN_POINT('',(0.0163156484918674,-6.57647664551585,4.60920831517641));
#560=CARTESIAN_POINT('',(0.00737807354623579,-6.67961930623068,4.4305599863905));
#561=CARTESIAN_POINT('',(-0.00127769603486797,-6.88599991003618,4.07309829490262));
#562=CARTESIAN_POINT('',(-0.000996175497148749,-6.98923785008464,3.89428493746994));
#563=CARTESIAN_POINT('',(0.00814502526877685,-7.18224506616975,3.5599866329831));
#564=CARTESIAN_POINT('',(0.0158896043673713,-7.27202796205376,3.40447809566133));
#565=CARTESIAN_POINT('',(0.0382011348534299,-7.45138347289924,3.09382523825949));
#566=CARTESIAN_POINT('',(0.0527685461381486,-7.5409560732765,2.93868094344));
#567=CARTESIAN_POINT('',(0.106360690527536,-7.80932710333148,2.47384868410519));
#568=CARTESIAN_POINT('',(0.155268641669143,-7.98765049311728,2.16498351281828));
#569=CARTESIAN_POINT('',(0.277539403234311,-8.34618890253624,1.5439767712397));
#570=CARTESIAN_POINT('',(0.351420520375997,-8.52635816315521,1.23191445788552));
#571=CARTESIAN_POINT('',(0.519100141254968,-8.88400987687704,0.612443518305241));
#572=CARTESIAN_POINT('',(0.612859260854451,-9.06149691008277,0.305026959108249));
#573=CARTESIAN_POINT('',(0.714597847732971,-9.23771977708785,-0.000199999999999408));
#574=B_SPLINE_CURVE_WITH_KNOTS('',3,(#548,#549,#550,#551,#552,#553,#554,#555,#556,#557,#558,
#559,#560,#561,#562,#563,#564,#565,#566,#567,#568,#569,#570,#571,#572,#573),.UNSPECIFIED.,.F.,
.F.,(4,2,2,2,2,2,2,2,2,2,2,2,4),(0.,0.633973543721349,1.26821965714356,2.53934712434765,
3.15934343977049,3.77928496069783,4.39852133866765,5.01773858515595,5.55680239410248,
6.09590254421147,7.17487077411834,8.27776850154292,9.37850115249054),.UNSPECIFIED.);
#575=CARTESIAN_POINT('',(0.714531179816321,-4.61880215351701,8.));
#576=VERTEX_POINT('',#575);
#577=EDGE_CURVE('E306',#576,#398,#574,.T.);
#578=ORIENTED_EDGE('',*,*,#577,.F.);
#579=EDGE_CURVE('E253',#402,#576,#537,.F.);
#580=ORIENTED_EDGE('',*,*,#579,.F.);
#581=EDGE_LOOP('',(#547,#578,#580));
#582=FACE_BOUND('',#581,.T.);
#583=ADVANCED_FACE('F469',(#582),#423,.T.);
#584=ORIENTED_EDGE('',*,*,#399,.F.);
#585=CARTESIAN_POINT('',(0.714597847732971,-9.23771977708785,0.000200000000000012));
#586=CARTESIAN_POINT('',(0.655990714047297,-9.13619343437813,-0.175648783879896));
#587=CARTESIAN_POINT('',(0.60004340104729,-9.03428856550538,-0.352153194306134));
#588=CARTESIAN_POINT('',(0.494201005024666,-8.82965122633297,-0.706595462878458));
#589=CARTESIAN_POINT('',(0.444308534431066,-8.72691841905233,-0.88453390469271));
#590=CARTESIAN_POINT('',(0.304692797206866,-8.41707512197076,-1.42119823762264));
#591=CARTESIAN_POINT('',(0.22528117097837,-8.20874154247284,-1.78204258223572));
#592=CARTESIAN_POINT('',(0.13216164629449,-7.89697436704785,-2.32203917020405));
#593=CARTESIAN_POINT('',(0.105634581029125,-7.79447216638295,-2.49957818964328));
#594=CARTESIAN_POINT('',(0.0611531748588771,-7.58900421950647,-2.8554591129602));
#595=CARTESIAN_POINT('',(0.0431980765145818,-7.4860385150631,-3.03380094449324));
#596=CARTESIAN_POINT('',(0.0163156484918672,-7.27992981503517,-3.39079168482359));
#597=CARTESIAN_POINT('',(0.00737807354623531,-7.17678715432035,-3.5694400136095));
#598=CARTESIAN_POINT('',(-0.00127769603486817,-6.97040655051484,-3.92690170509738));
#599=CARTESIAN_POINT('',(-0.000996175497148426,-6.86716861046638,-4.10571506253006));
#600=CARTESIAN_POINT('',(0.00814502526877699,-6.67416139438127,-4.4400133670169));
#601=CARTESIAN_POINT('',(0.0158896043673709,-6.58437849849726,-4.59552190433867));
#602=CARTESIAN_POINT('',(0.0382011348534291,-6.40502298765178,-4.90617476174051));
#603=CARTESIAN_POINT('',(0.052768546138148,-6.31545038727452,-5.06131905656));
#604=CARTESIAN_POINT('',(0.106360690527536,-6.04707935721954,-5.52615131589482));
#605=CARTESIAN_POINT('',(0.155268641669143,-5.86875596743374,-5.83501648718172));
#606=CARTESIAN_POINT('',(0.277539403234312,-5.51021755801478,-6.4560232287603));
#607=CARTESIAN_POINT('',(0.351420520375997,-5.3300482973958,-6.76808554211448));
#608=CARTESIAN_POINT('',(0.519100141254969,-4.97239658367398,-7.38755648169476));
#609=CARTESIAN_POINT('',(0.612859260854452,-4.79490955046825,-7.69497304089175));
#610=CARTESIAN_POINT('',(0.714597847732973,-4.61868668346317,-8.00020000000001));
#611=B_SPLINE_CURVE_WITH_KNOTS('',3,(#585,#586,#587,#588,#589,#590,#591,#592,#593,#594,#595,
#596,#597,#598,#599,#600,#601,#602,#603,#604,#605,#606,#607,#608,#609,#610),.UNSPECIFIED.,.F.,
.F.,(4,2,2,2,2,2,2,2,2,2,2,2,4),(0.,0.633973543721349,1.26821965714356,2.53934712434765,
3.15934343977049,3.77928496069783,4.39852133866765,5.01773858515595,5.55680239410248,
6.09590254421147,7.17487077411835,8.27776850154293,9.37850115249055),.UNSPECIFIED.);
#612=CARTESIAN_POINT('',(0.714531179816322,-9.23760430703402,0.));
#613=VERTEX_POINT('',#612);
#614=EDGE_CURVE('E310',#613,#394,#611,.T.);
#615=ORIENTED_EDGE('',*,*,#614,.F.);
#616=EDGE_CURVE('E307',#398,#613,#574,.T.);
#617=ORIENTED_EDGE('',*,*,#616,.F.);
#618=EDGE_LOOP('',(#584,#615,#617));
#619=FACE_BOUND('',#618,.T.);
#620=ADVANCED_FACE('F338',(#619),#423,.T.);
#621=CARTESIAN_POINT('',(3.82821364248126,-12.2497439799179,-8.00000000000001));
#622=CARTESIAN_POINT('',(3.6584725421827,-11.8984987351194,-8.00000000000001));
#623=CARTESIAN_POINT('',(3.49041880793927,-11.5464230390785,-8.00000000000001));
#624=CARTESIAN_POINT('',(3.15865029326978,-10.840161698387,-8.00000000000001));
#625=CARTESIAN_POINT('',(2.99493626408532,-10.4859757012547,-8.00000000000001));
#626=CARTESIAN_POINT('',(2.67194892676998,-9.77313142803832,-8.00000000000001));
#627=CARTESIAN_POINT('',(2.51270639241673,-9.41445915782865,-8.00000000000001));
#628=CARTESIAN_POINT('',(2.2010611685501,-8.69416671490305,-8.00000000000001));
#629=CARTESIAN_POINT('',(2.04865812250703,-8.33254669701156,-8.00000000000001));
#630=CARTESIAN_POINT('',(1.75070130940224,-7.60129405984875,-8.00000000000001));
#631=CARTESIAN_POINT('',(1.60525460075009,-7.23161757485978,-8.));
#632=CARTESIAN_POINT('',(1.32575242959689,-6.48790521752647,-8.));
#633=CARTESIAN_POINT('',(1.19169823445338,-6.11386886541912,-8.));
#634=CARTESIAN_POINT('',(0.93858361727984,-5.36160531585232,-8.));
#635=CARTESIAN_POINT('',(0.819491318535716,-4.9833889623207,-8.));
#636=CARTESIAN_POINT('',(0.600166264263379,-4.22159300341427,-8.));
#637=CARTESIAN_POINT('',(0.499927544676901,-3.83801513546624,-8.));
#638=CARTESIAN_POINT('',(0.323183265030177,-3.06517005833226,-8.));
#639=CARTESIAN_POINT('',(0.246684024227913,-2.67590136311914,-8.));
#640=CARTESIAN_POINT('',(0.153570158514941,-2.08857290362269,-8.));
#641=CARTESIAN_POINT('',(0.126136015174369,-1.89220175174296,-8.));
#642=CARTESIAN_POINT('',(0.0790191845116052,-1.49853877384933,-8.));
#643=CARTESIAN_POINT('',(0.059335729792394,-1.30124704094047,-8.));
#644=CARTESIAN_POINT('',(0.0282499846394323,-0.907261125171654,-8.));
#645=CARTESIAN_POINT('',(0.0167962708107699,-0.710571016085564,-8.));
#646=CARTESIAN_POINT('',(0.00223056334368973,-0.316882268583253,-8.));
#647=CARTESIAN_POINT('',(-0.000881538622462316,-0.119883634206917,-8.));
#648=CARTESIAN_POINT('',(0.00131013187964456,0.274012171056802,-8.));
#649=CARTESIAN_POINT('',(0.00661154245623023,0.470909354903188,-8.));
#650=CARTESIAN_POINT('',(0.0254984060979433,0.86430865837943,-8.));
#651=CARTESIAN_POINT('',(0.0390842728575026,1.06081075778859,-8.));
#652=CARTESIAN_POINT('',(0.0817685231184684,1.53707134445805,-8.));
#653=CARTESIAN_POINT('',(0.115017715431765,1.81646391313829,-8.));
#654=CARTESIAN_POINT('',(0.196418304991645,2.37310809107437,-8.));
#655=CARTESIAN_POINT('',(0.244573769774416,2.65035909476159,-8.));
#656=CARTESIAN_POINT('',(0.354078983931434,3.20249141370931,-8.));
#657=CARTESIAN_POINT('',(0.415441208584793,3.47737023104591,-8.));
#658=CARTESIAN_POINT('',(0.549487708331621,4.02429975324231,-8.));
#659=CARTESIAN_POINT('',(0.622170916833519,4.29635072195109,-8.));
#660=CARTESIAN_POINT('',(0.779020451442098,4.84432510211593,-8.));
#661=CARTESIAN_POINT('',(0.863424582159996,5.12017997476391,-8.));
#662=CARTESIAN_POINT('',(1.04057245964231,5.66897392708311,-8.));
#663=CARTESIAN_POINT('',(1.13331045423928,5.94191487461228,-8.));
#664=CARTESIAN_POINT('',(1.32521046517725,6.48378576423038,-8.));
#665=CARTESIAN_POINT('',(1.42433338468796,6.75272963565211,-8.));
#666=CARTESIAN_POINT('',(1.62839717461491,7.28853074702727,-8.));
#667=CARTESIAN_POINT('',(1.73334039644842,7.55538709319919,-8.));
#668=CARTESIAN_POINT('',(1.84061801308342,7.82127397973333,-8.));
#669=B_SPLINE_CURVE_WITH_KNOTS('',3,(#621,#622,#623,#624,#625,#626,#627,#628,#629,#630,#631,
#632,#633,#634,#635,#636,#637,#638,#639,#640,#641,#642,#643,#644,#645,#646,#647,#648,#649,#650,
#651,#652,#653,#654,#655,#656,#657,#658,#659,#660,#661,#662,#663,#664,#665,#666,#667,#668),
.UNSPECIFIED.,.F.,.F.,(4,2,2,2,2,2,2,2,2,2,2,2,2,2,2,2,2,2,2,2,2,2,2,4),(0.,1.17034358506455,
2.34088846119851,3.51813189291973,4.69531388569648,5.88694801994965,7.0787145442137,
8.26789729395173,9.45670322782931,10.6458253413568,11.2405311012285,11.8351779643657,
12.4260760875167,13.0169665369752,13.6076911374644,14.1984452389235,15.0420672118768,
15.8859195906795,16.7305726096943,17.5751460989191,18.4404219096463,19.3051050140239,
20.1649211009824,21.0250871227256),.UNSPECIFIED.);
#670=CARTESIAN_POINT('',(0.714531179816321,4.61880215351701,-8.));
#671=VERTEX_POINT('',#670);
#672=EDGE_CURVE('E177',#390,#671,#669,.T.);
#673=ORIENTED_EDGE('',*,*,#672,.F.);
#674=ORIENTED_EDGE('',*,*,#391,.F.);
#675=EDGE_CURVE('E264',#671,#388,#482,.T.);
#676=ORIENTED_EDGE('',*,*,#675,.F.);
#677=EDGE_LOOP('',(#673,#674,#676));
#678=FACE_BOUND('',#677,.T.);
#679=ADVANCED_FACE('F157',(#678),#423,.T.);
#680=ORIENTED_EDGE('',*,*,#395,.F.);
#681=CARTESIAN_POINT('',(0.714531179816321,-4.61880215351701,-8.));
#682=VERTEX_POINT('',#681);
#683=EDGE_CURVE('E339',#682,#390,#669,.T.);
#684=ORIENTED_EDGE('',*,*,#683,.F.);
#685=EDGE_CURVE('E314',#394,#682,#611,.T.);
#686=ORIENTED_EDGE('',*,*,#685,.F.);
#687=EDGE_LOOP('',(#680,#684,#686));
#688=FACE_BOUND('',#687,.T.);
#689=ADVANCED_FACE('F171',(#688),#423,.T.);
#690=CARTESIAN_POINT('',(7.5,-4.61880215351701,-8.));
#691=DIRECTION('',(0.,0.,1.));
#692=DIRECTION('',(0.,-1.,0.));
#693=AXIS2_PLACEMENT_3D('',#690,#691,#692);
#694=PLANE('',#693);
#695=DIRECTION('',(-1.,0.,0.));
#696=VECTOR('',#695,1.);
#697=CARTESIAN_POINT('',(7.5,4.61880215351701,-8.));
#698=LINE('',#697,#696);
#699=EDGE_CURVE('E265',#188,#671,#698,.T.);
#700=ORIENTED_EDGE('',*,*,#699,.F.);
#701=ORIENTED_EDGE('',*,*,#189,.T.);
#702=ORIENTED_EDGE('',*,*,#151,.T.);
#703=DIRECTION('',(-1.,0.,0.));
#704=VECTOR('',#703,1.);
#705=CARTESIAN_POINT('',(7.5,-4.61880215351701,-8.));
#706=LINE('',#705,#704);
#707=EDGE_CURVE('E267',#150,#682,#706,.T.);
#708=ORIENTED_EDGE('',*,*,#707,.T.);
#709=ORIENTED_EDGE('',*,*,#683,.T.);
#710=ORIENTED_EDGE('',*,*,#672,.T.);
#711=EDGE_LOOP('',(#700,#701,#702,#708,#709,#710));
#712=FACE_BOUND('',#711,.T.);
#713=ADVANCED_FACE('F166',(#712),#694,.F.);
#714=CARTESIAN_POINT('',(7.5,-9.23760430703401,0.));
#715=DIRECTION('',(0.,0.866025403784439,0.5));
#716=DIRECTION('',(0.,-0.5,0.866025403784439));
#717=AXIS2_PLACEMENT_3D('',#714,#715,#716);
#718=PLANE('',#717);
#719=ORIENTED_EDGE('',*,*,#707,.F.);
#720=ORIENTED_EDGE('',*,*,#181,.T.);
#721=ORIENTED_EDGE('',*,*,#225,.T.);
#722=DIRECTION('',(-1.,0.,0.));
#723=VECTOR('',#722,1.);
#724=CARTESIAN_POINT('',(7.5,-9.23760430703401,0.));
#725=LINE('',#724,#723);
#726=EDGE_CURVE('E269',#224,#613,#725,.T.);
#727=ORIENTED_EDGE('',*,*,#726,.T.);
#728=ORIENTED_EDGE('',*,*,#614,.T.);
#729=ORIENTED_EDGE('',*,*,#685,.T.);
#730=EDGE_LOOP('',(#719,#720,#721,#727,#728,#729));
#731=FACE_BOUND('',#730,.T.);
#732=ADVANCED_FACE('F170',(#731),#718,.F.);
#733=CARTESIAN_POINT('',(7.5,-4.61880215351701,8.));
#734=DIRECTION('',(0.,0.866025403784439,-0.5));
#735=DIRECTION('',(0.,0.5,0.866025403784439));
#736=AXIS2_PLACEMENT_3D('',#733,#734,#735);
#737=PLANE('',#736);
#738=ORIENTED_EDGE('',*,*,#726,.F.);
#739=ORIENTED_EDGE('',*,*,#255,.T.);
#740=ORIENTED_EDGE('',*,*,#262,.T.);
#741=DIRECTION('',(-1.,0.,0.));
#742=VECTOR('',#741,1.);
#743=CARTESIAN_POINT('',(7.5,-4.61880215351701,8.));
#744=LINE('',#743,#742);
#745=EDGE_CURVE('E271',#261,#576,#744,.T.);
#746=ORIENTED_EDGE('',*,*,#745,.T.);
#747=ORIENTED_EDGE('',*,*,#577,.T.);
#748=ORIENTED_EDGE('',*,*,#616,.T.);
#749=EDGE_LOOP('',(#738,#739,#740,#746,#747,#748));
#750=FACE_BOUND('',#749,.T.);
#751=ADVANCED_FACE('F318',(#750),#737,.F.);
#752=CARTESIAN_POINT('',(7.5,4.618802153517,8.));
#753=DIRECTION('',(0.,0.,-1.));
#754=DIRECTION('',(0.,1.,0.));
#755=AXIS2_PLACEMENT_3D('',#752,#753,#754);
#756=PLANE('',#755);
#757=ORIENTED_EDGE('',*,*,#745,.F.);
#758=ORIENTED_EDGE('',*,*,#314,.T.);
#759=ORIENTED_EDGE('',*,*,#351,.T.);
#760=DIRECTION('',(-1.,0.,0.));
#761=VECTOR('',#760,1.);
#762=CARTESIAN_POINT('',(7.5,4.618802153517,8.));
#763=LINE('',#762,#761);
#764=EDGE_CURVE('E273',#348,#539,#763,.T.);
#765=ORIENTED_EDGE('',*,*,#764,.T.);
#766=ORIENTED_EDGE('',*,*,#540,.T.);
#767=ORIENTED_EDGE('',*,*,#579,.T.);
#768=EDGE_LOOP('',(#757,#758,#759,#765,#766,#767));
#769=FACE_BOUND('',#768,.T.);
#770=ADVANCED_FACE('F238',(#769),#756,.F.);
#771=CARTESIAN_POINT('',(7.5,9.23760430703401,0.));
#772=DIRECTION('',(0.,-0.866025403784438,-0.5));
#773=DIRECTION('',(0.,0.5,-0.866025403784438));
#774=AXIS2_PLACEMENT_3D('',#771,#772,#773);
#775=PLANE('',#774);
#776=ORIENTED_EDGE('',*,*,#764,.F.);
#777=ORIENTED_EDGE('',*,*,#349,.T.);
#778=ORIENTED_EDGE('',*,*,#361,.T.);
#779=DIRECTION('',(-1.,0.,0.));
#780=VECTOR('',#779,1.);
#781=CARTESIAN_POINT('',(7.5,9.23760430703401,0.));
#782=LINE('',#781,#780);
#783=EDGE_CURVE('E274',#358,#453,#782,.T.);
#784=ORIENTED_EDGE('',*,*,#783,.T.);
#785=ORIENTED_EDGE('',*,*,#454,.T.);
#786=ORIENTED_EDGE('',*,*,#542,.T.);
#787=EDGE_LOOP('',(#776,#777,#778,#784,#785,#786));
#788=FACE_BOUND('',#787,.T.);
#789=ADVANCED_FACE('F235',(#788),#775,.F.);
#790=CARTESIAN_POINT('',(7.5,4.61880215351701,-8.));
#791=DIRECTION('',(0.,-0.866025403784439,0.5));
#792=DIRECTION('',(0.,-0.5,-0.866025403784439));
#793=AXIS2_PLACEMENT_3D('',#790,#791,#792);
#794=PLANE('',#793);
#795=ORIENTED_EDGE('',*,*,#783,.F.);
#796=ORIENTED_EDGE('',*,*,#359,.T.);
#797=ORIENTED_EDGE('',*,*,#218,.T.);
#798=ORIENTED_EDGE('',*,*,#699,.T.);
#799=ORIENTED_EDGE('',*,*,#675,.T.);
#800=ORIENTED_EDGE('',*,*,#483,.T.);
#801=EDGE_LOOP('',(#795,#796,#797,#798,#799,#800));
#802=FACE_BOUND('',#801,.T.);
#803=ADVANCED_FACE('F140',(#802),#794,.F.);
#804=CARTESIAN_POINT('',(7.9,0.,0.));
#805=DIRECTION('',(1.,0.,0.));
#806=DIRECTION('',(0.,0.,-1.));
#807=AXIS2_PLACEMENT_3D('',#804,#805,#806);
#808=TOROIDAL_SURFACE('',#807,5.15,0.4);
#809=ORIENTED_EDGE('',*,*,#31,.F.);
#810=EDGE_LOOP('',(#809));
#811=FACE_BOUND('',#810,.T.);
#812=ORIENTED_EDGE('',*,*,#59,.F.);
#813=EDGE_LOOP('',(#812));
#814=FACE_BOUND('',#813,.T.);
#815=ADVANCED_FACE('F38',(#811,#814),#808,.F.);
#816=CARTESIAN_POINT('',(10.4863126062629,-24.8480524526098,0.));
#817=DIRECTION('',(0.,0.,-1.));
#818=DIRECTION('',(0.,1.,0.));
#819=AXIS2_PLACEMENT_3D('',#816,#817,#818);
#820=CIRCLE('',#819,32.);
#821=TRIMMED_CURVE('',#820,(PARAMETER_VALUE(-0.681701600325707)),
(PARAMETER_VALUE(0.681701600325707)),.T.,.PARAMETER.);
#822=CARTESIAN_POINT('',(10.4863126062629,0.,0.));
#823=DIRECTION('',(1.,0.,0.));
#824=AXIS1_PLACEMENT('',#822,#823);
#825=SURFACE_OF_REVOLUTION('',#821,#824);
#826=ORIENTED_EDGE('',*,*,#42,.T.);
#827=EDGE_LOOP('',(#826));
#828=FACE_BOUND('',#827,.T.);
#829=CARTESIAN_POINT('',(30.65,0.,0.));
#830=VERTEX_POINT('',#829);
#831=VERTEX_LOOP('',#830);
#832=FACE_BOUND('',#831,.T.);
#833=ADVANCED_FACE('F128',(#828,#832),#825,.T.);
#834=CARTESIAN_POINT('',(0.,0.,0.));
#835=DIRECTION('',(1.,0.,0.));
#836=DIRECTION('',(0.,0.,-1.));
#837=AXIS2_PLACEMENT_3D('',#834,#835,#836);
#838=CYLINDRICAL_SURFACE('',#837,6.66666666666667);
#839=CARTESIAN_POINT('',(1.25,0.,0.));
#840=DIRECTION('',(1.,0.,0.));
#841=DIRECTION('',(0.,0.,-1.));
#842=AXIS2_PLACEMENT_3D('',#839,#840,#841);
#843=CIRCLE('',#842,6.66666666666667);
#844=CARTESIAN_POINT('',(1.25,0.,-6.66666666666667));
#845=VERTEX_POINT('',#844);
#846=EDGE_CURVE('E363',#845,#845,#843,.T.);
#847=ORIENTED_EDGE('',*,*,#846,.T.);
#848=EDGE_LOOP('',(#847));
#849=FACE_BOUND('',#848,.T.);
#850=ORIENTED_EDGE('',*,*,#378,.F.);
#851=EDGE_LOOP('',(#850));
#852=FACE_BOUND('',#851,.T.);
#853=ADVANCED_FACE('F130',(#849,#852),#838,.F.);
#854=CARTESIAN_POINT('',(1.25,6.66666666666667,0.));
#855=DIRECTION('',(1.,0.,0.));
#856=DIRECTION('',(0.,0.,-1.));
#857=AXIS2_PLACEMENT_3D('',#854,#855,#856);
#858=PLANE('',#857);
#859=ORIENTED_EDGE('',*,*,#846,.F.);
#860=EDGE_LOOP('',(#859));
#861=FACE_BOUND('',#860,.T.);
#862=ADVANCED_FACE('F137',(#861),#858,.F.);
#863=CLOSED_SHELL('',(#46,#94,#185,#222,#259,#318,#355,#365,#418,#487,#546,#583,#620,#679,#689,
#713,#732,#751,#770,#789,#803,#815,#833,#853,#862));
#864=MANIFOLD_SOLID_BREP('B2',#863);
#865=ADVANCED_BREP_SHAPE_REPRESENTATION('',(#18,#864),#14);
#866=SHAPE_DEFINITION_REPRESENTATION(#9,#865);
ENDSEC;
END-ISO-10303-21;
